One B-rep face of a CAD part: STEP entity #78930.
In plain terms, the planar face has unit normal (0, 0, 1).
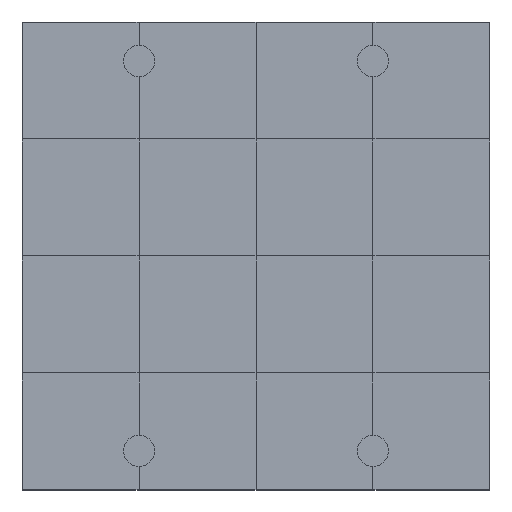
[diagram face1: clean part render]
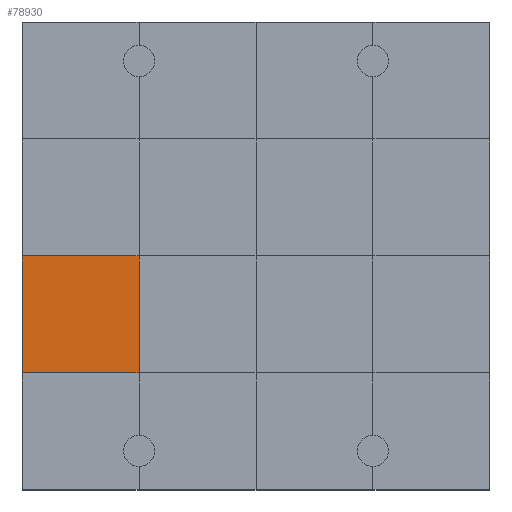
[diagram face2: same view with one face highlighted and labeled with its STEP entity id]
Its self-contained STEP definition (entity closure, numbers rounded to 3 decimals):
#78480 = VERTEX_POINT('',#78481);
#78481 = CARTESIAN_POINT('',(0.,3.,1.2));
#78495 = PLANE('',#78496);
#78496 = AXIS2_PLACEMENT_3D('',#78497,#78498,#78499);
#78497 = CARTESIAN_POINT('',(0.,3.,0.));
#78498 = DIRECTION('',(1.,0.,-0.));
#78499 = DIRECTION('',(0.,0.,1.));
#78521 = PLANE('',#78522);
#78522 = AXIS2_PLACEMENT_3D('',#78523,#78524,#78525);
#78523 = CARTESIAN_POINT('',(0.,0.,1.2));
#78524 = DIRECTION('',(0.,0.,1.));
#78525 = DIRECTION('',(1.,0.,-0.));
#78672 = VERTEX_POINT('',#78673);
#78673 = CARTESIAN_POINT('',(3.,3.,1.2));
#78694 = EDGE_CURVE('',#78480,#78672,#78695,.T.);
#78695 = SURFACE_CURVE('',#78696,(#78700,#78707),.PCURVE_S1.);
#78696 = LINE('',#78697,#78698);
#78697 = CARTESIAN_POINT('',(0.,3.,1.2));
#78698 = VECTOR('',#78699,1.);
#78699 = DIRECTION('',(1.,0.,-0.));
#78700 = PCURVE('',#78521,#78701);
#78701 = DEFINITIONAL_REPRESENTATION('',(#78702),#78706);
#78702 = LINE('',#78703,#78704);
#78703 = CARTESIAN_POINT('',(0.,3.));
#78704 = VECTOR('',#78705,1.);
#78705 = DIRECTION('',(1.,0.));
#78706 = ( GEOMETRIC_REPRESENTATION_CONTEXT(2) 
PARAMETRIC_REPRESENTATION_CONTEXT() REPRESENTATION_CONTEXT('2D SPACE',''
  ) );
#78707 = PCURVE('',#78708,#78713);
#78708 = PLANE('',#78709);
#78709 = AXIS2_PLACEMENT_3D('',#78710,#78711,#78712);
#78710 = CARTESIAN_POINT('',(0.,3.,1.2));
#78711 = DIRECTION('',(0.,0.,1.));
#78712 = DIRECTION('',(1.,0.,-0.));
#78713 = DEFINITIONAL_REPRESENTATION('',(#78714),#78718);
#78714 = LINE('',#78715,#78716);
#78715 = CARTESIAN_POINT('',(0.,0.));
#78716 = VECTOR('',#78717,1.);
#78717 = DIRECTION('',(1.,0.));
#78718 = ( GEOMETRIC_REPRESENTATION_CONTEXT(2) 
PARAMETRIC_REPRESENTATION_CONTEXT() REPRESENTATION_CONTEXT('2D SPACE',''
  ) );
#78753 = VERTEX_POINT('',#78754);
#78754 = CARTESIAN_POINT('',(0.,6.,1.2));
#78780 = EDGE_CURVE('',#78480,#78753,#78781,.T.);
#78781 = SURFACE_CURVE('',#78782,(#78786,#78793),.PCURVE_S1.);
#78782 = LINE('',#78783,#78784);
#78783 = CARTESIAN_POINT('',(0.,3.,1.2));
#78784 = VECTOR('',#78785,1.);
#78785 = DIRECTION('',(-0.,1.,0.));
#78786 = PCURVE('',#78495,#78787);
#78787 = DEFINITIONAL_REPRESENTATION('',(#78788),#78792);
#78788 = LINE('',#78789,#78790);
#78789 = CARTESIAN_POINT('',(1.2,0.));
#78790 = VECTOR('',#78791,1.);
#78791 = DIRECTION('',(0.,-1.));
#78792 = ( GEOMETRIC_REPRESENTATION_CONTEXT(2) 
PARAMETRIC_REPRESENTATION_CONTEXT() REPRESENTATION_CONTEXT('2D SPACE',''
  ) );
#78793 = PCURVE('',#78708,#78794);
#78794 = DEFINITIONAL_REPRESENTATION('',(#78795),#78799);
#78795 = LINE('',#78796,#78797);
#78796 = CARTESIAN_POINT('',(0.,0.));
#78797 = VECTOR('',#78798,1.);
#78798 = DIRECTION('',(0.,1.));
#78799 = ( GEOMETRIC_REPRESENTATION_CONTEXT(2) 
PARAMETRIC_REPRESENTATION_CONTEXT() REPRESENTATION_CONTEXT('2D SPACE',''
  ) );
#78930 = ADVANCED_FACE('',(#78931),#78708,.T.);
#78931 = FACE_BOUND('',#78932,.T.);
#78932 = EDGE_LOOP('',(#78933,#78934,#78935,#78963));
#78933 = ORIENTED_EDGE('',*,*,#78780,.F.);
#78934 = ORIENTED_EDGE('',*,*,#78694,.T.);
#78935 = ORIENTED_EDGE('',*,*,#78936,.T.);
#78936 = EDGE_CURVE('',#78672,#78937,#78939,.T.);
#78937 = VERTEX_POINT('',#78938);
#78938 = CARTESIAN_POINT('',(3.,6.,1.2));
#78939 = SURFACE_CURVE('',#78940,(#78944,#78951),.PCURVE_S1.);
#78940 = LINE('',#78941,#78942);
#78941 = CARTESIAN_POINT('',(3.,3.,1.2));
#78942 = VECTOR('',#78943,1.);
#78943 = DIRECTION('',(-0.,1.,0.));
#78944 = PCURVE('',#78708,#78945);
#78945 = DEFINITIONAL_REPRESENTATION('',(#78946),#78950);
#78946 = LINE('',#78947,#78948);
#78947 = CARTESIAN_POINT('',(3.,0.));
#78948 = VECTOR('',#78949,1.);
#78949 = DIRECTION('',(0.,1.));
#78950 = ( GEOMETRIC_REPRESENTATION_CONTEXT(2) 
PARAMETRIC_REPRESENTATION_CONTEXT() REPRESENTATION_CONTEXT('2D SPACE',''
  ) );
#78951 = PCURVE('',#78952,#78957);
#78952 = PLANE('',#78953);
#78953 = AXIS2_PLACEMENT_3D('',#78954,#78955,#78956);
#78954 = CARTESIAN_POINT('',(3.,3.,1.2));
#78955 = DIRECTION('',(0.,0.,1.));
#78956 = DIRECTION('',(1.,0.,-0.));
#78957 = DEFINITIONAL_REPRESENTATION('',(#78958),#78962);
#78958 = LINE('',#78959,#78960);
#78959 = CARTESIAN_POINT('',(0.,0.));
#78960 = VECTOR('',#78961,1.);
#78961 = DIRECTION('',(0.,1.));
#78962 = ( GEOMETRIC_REPRESENTATION_CONTEXT(2) 
PARAMETRIC_REPRESENTATION_CONTEXT() REPRESENTATION_CONTEXT('2D SPACE',''
  ) );
#78963 = ORIENTED_EDGE('',*,*,#78964,.F.);
#78964 = EDGE_CURVE('',#78753,#78937,#78965,.T.);
#78965 = SURFACE_CURVE('',#78966,(#78970,#78977),.PCURVE_S1.);
#78966 = LINE('',#78967,#78968);
#78967 = CARTESIAN_POINT('',(0.,6.,1.2));
#78968 = VECTOR('',#78969,1.);
#78969 = DIRECTION('',(1.,0.,-0.));
#78970 = PCURVE('',#78708,#78971);
#78971 = DEFINITIONAL_REPRESENTATION('',(#78972),#78976);
#78972 = LINE('',#78973,#78974);
#78973 = CARTESIAN_POINT('',(0.,3.));
#78974 = VECTOR('',#78975,1.);
#78975 = DIRECTION('',(1.,0.));
#78976 = ( GEOMETRIC_REPRESENTATION_CONTEXT(2) 
PARAMETRIC_REPRESENTATION_CONTEXT() REPRESENTATION_CONTEXT('2D SPACE',''
  ) );
#78977 = PCURVE('',#78978,#78983);
#78978 = PLANE('',#78979);
#78979 = AXIS2_PLACEMENT_3D('',#78980,#78981,#78982);
#78980 = CARTESIAN_POINT('',(0.,6.,1.2));
#78981 = DIRECTION('',(0.,0.,1.));
#78982 = DIRECTION('',(1.,0.,-0.));
#78983 = DEFINITIONAL_REPRESENTATION('',(#78984),#78988);
#78984 = LINE('',#78985,#78986);
#78985 = CARTESIAN_POINT('',(0.,0.));
#78986 = VECTOR('',#78987,1.);
#78987 = DIRECTION('',(1.,0.));
#78988 = ( GEOMETRIC_REPRESENTATION_CONTEXT(2) 
PARAMETRIC_REPRESENTATION_CONTEXT() REPRESENTATION_CONTEXT('2D SPACE',''
  ) );
